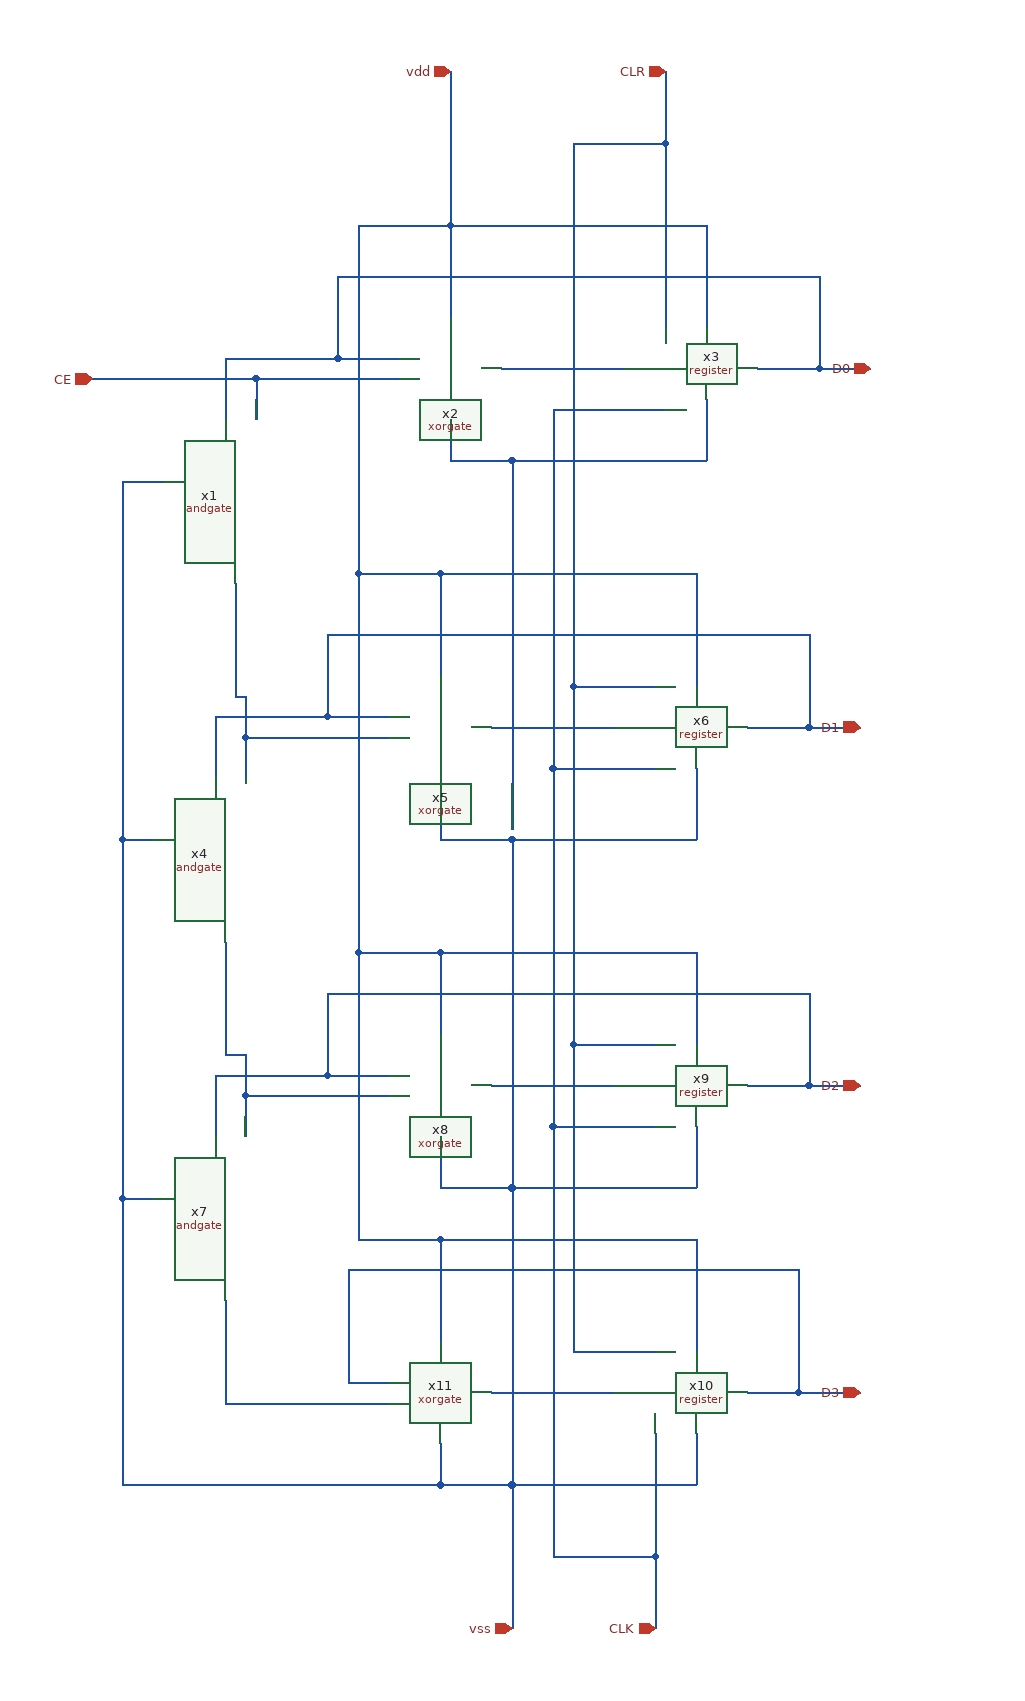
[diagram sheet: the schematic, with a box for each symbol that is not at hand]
v {xschem version=3.4.8RC file_version=1.3}
G {}
K {}
V {}
S {}
F {}
E {}
N -110 -120 30 -120 {lab=CE}
N -110 -120 -110 -80 {lab=CE}
N -270 -120 -110 -120 {lab=CE}
N -140 -140 -140 -80 {lab=D1}
N -30 -140 30 -140 {lab=D1}
N 130 -130 250 -130 {lab=#net1}
N 440 -130 490 -130 {lab=D1}
N 440 -220 440 -130 {lab=D1}
N 380 -130 440 -130 {lab=D1}
N -30 -220 440 -220 {lab=D1}
N -30 -220 -30 -140 {lab=D1}
N -140 -140 -30 -140 {lab=D1}
N -120 230 20 230 {lab=#net2}
N -120 230 -120 270 {lab=#net2}
N -150 210 -150 270 {lab=D1}
N -40 210 20 210 {lab=D1}
N 120 220 240 220 {lab=#net3}
N 430 220 480 220 {lab=D1}
N 430 130 430 220 {lab=D1}
N 370 220 430 220 {lab=D1}
N -40 130 430 130 {lab=D1}
N -40 130 -40 210 {lab=D1}
N -150 210 -40 210 {lab=D1}
N -130 80 -130 190 {lab=#net2}
N -130 190 -120 190 {lab=#net2}
N -120 190 -120 230 {lab=#net2}
N -120 580 20 580 {lab=#net4}
N -120 580 -120 620 {lab=#net4}
N -150 560 -150 620 {lab=D2}
N -40 560 20 560 {lab=D2}
N 120 570 240 570 {lab=#net5}
N 430 570 480 570 {lab=D2}
N 430 480 430 570 {lab=D2}
N 370 570 430 570 {lab=D2}
N -40 480 430 480 {lab=D2}
N -40 480 -40 560 {lab=D2}
N -150 560 -40 560 {lab=D2}
N -140 430 -140 540 {lab=#net4}
N -140 540 -120 540 {lab=#net4}
N -120 540 -120 580 {lab=#net4}
N 120 870 240 870 {lab=#net6}
N 420 870 480 870 {lab=D3}
N -140 780 -140 880 {lab=#net7}
N -140 880 20 880 {lab=#net7}
N -20 860 20 860 {lab=D3}
N -20 750 -20 860 {lab=D3}
N -20 750 420 750 {lab=D3}
N 420 750 420 870 {lab=D3}
N 370 870 420 870 {lab=D3}
N 280 1030 280 1100 {lab=CLK}
N 180 610 280 610 {lab=CLK}
N 180 1030 280 1030 {lab=CLK}
N 280 910 280 1030 {lab=CLK}
N 180 260 280 260 {lab=CLK}
N 180 610 180 1030 {lab=CLK}
N 180 260 180 610 {lab=CLK}
N 180 -90 290 -90 {lab=CLK}
N 180 -90 180 260 {lab=CLK}
N 290 -350 290 -170 {lab=CLR}
N 200 180 280 180 {lab=CLR}
N 200 -350 200 180 {lab=CLR}
N 200 -350 290 -350 {lab=CLR}
N 290 -420 290 -350 {lab=CLR}
N 200 530 280 530 {lab=CLR}
N 200 180 200 530 {lab=CLR}
N 200 830 280 830 {lab=CLR}
N 200 530 200 830 {lab=CLR}
N 320 260 320 330 {lab=vss}
N 70 270 70 330 {lab=vss}
N 140 330 140 670 {lab=vss}
N 140 330 320 330 {lab=vss}
N 70 330 140 330 {lab=vss}
N 320 610 320 670 {lab=vss}
N 140 670 320 670 {lab=vss}
N 70 620 70 670 {lab=vss}
N 70 670 140 670 {lab=vss}
N 140 960 140 1100 {lab=vss}
N 140 670 140 960 {lab=vss}
N 320 910 320 960 {lab=vss}
N 140 960 320 960 {lab=vss}
N 70 920 70 960 {lab=vss}
N 70 960 140 960 {lab=vss}
N -240 330 -210 330 {lab=vss}
N -240 680 -210 680 {lab=vss}
N -240 680 -240 960 {lab=vss}
N -240 960 70 960 {lab=vss}
N 80 -80 80 -40 {lab=#net8}
N 80 -40 140 -40 {lab=#net8}
N 140 -40 140 320 {lab=#net8}
N 140 -40 330 -40 {lab=#net8}
N 330 -100 330 -40 {lab=#net8}
N -240 -20 -200 -20 {lab=vss}
N -240 330 -240 680 {lab=vss}
N -240 -20 -240 330 {lab=vss}
N 80 -270 80 -180 {lab=vdd}
N 330 -270 330 -170 {lab=vdd}
N 80 -270 330 -270 {lab=vdd}
N 80 -420 80 -270 {lab=vdd}
N 70 70 70 170 {lab=vdd}
N -10 70 70 70 {lab=vdd}
N -10 -270 80 -270 {lab=vdd}
N -10 -270 -10 70 {lab=vdd}
N 70 70 320 70 {lab=vdd}
N 320 70 320 180 {lab=vdd}
N 70 440 70 520 {lab=vdd}
N -10 70 -10 440 {lab=vdd}
N -10 440 70 440 {lab=vdd}
N 70 440 320 440 {lab=vdd}
N 320 440 320 530 {lab=vdd}
N -10 440 -10 720 {lab=vdd}
N -10 720 70 720 {lab=vdd}
N 70 720 70 820 {lab=vdd}
N 70 720 320 720 {lab=vdd}
N 320 720 320 830 {lab=vdd}
C {blocks/andgate/schematic/andgate.sym} -130 70 1 0 {name=x1}
C {blocks/xorgate/schematic/xorgate.sym} 30 -130 0 0 {name=x2}
C {blocks/register/schematic/register.sym} 340 -130 0 0 {name=x3}
C {iopin.sym} -270 -120 2 0 {name=p2 lab=CE}
C {iopin.sym} 280 1100 1 0 {name=p1 lab=CLK}
C {iopin.sym} 290 -420 3 0 {name=p3 lab=CLR}
C {iopin.sym} 80 -420 3 0 {name=p5 lab=vdd}
C {iopin.sym} 140 1100 1 0 {name=p7 lab=vss}
C {iopin.sym} 490 -130 0 0 {name=p13 lab=D0}
C {blocks/andgate/schematic/andgate.sym} -140 420 1 0 {name=x4}
C {blocks/xorgate/schematic/xorgate.sym} 20 220 0 0 {name=x5}
C {blocks/register/schematic/register.sym} 330 220 0 0 {name=x6}
C {iopin.sym} 480 220 0 0 {name=p4 lab=D1}
C {blocks/andgate/schematic/andgate.sym} -140 770 1 0 {name=x7}
C {blocks/xorgate/schematic/xorgate.sym} 20 570 0 0 {name=x8}
C {blocks/register/schematic/register.sym} 330 570 0 0 {name=x9}
C {iopin.sym} 480 570 0 0 {name=p6 lab=D2}
C {blocks/register/schematic/register.sym} 330 870 0 0 {name=x10}
C {iopin.sym} 480 870 0 0 {name=p8 lab=D3}
C {blocks/xorgate/schematic/xorgate.sym} 20 870 0 0 {name=x11}
